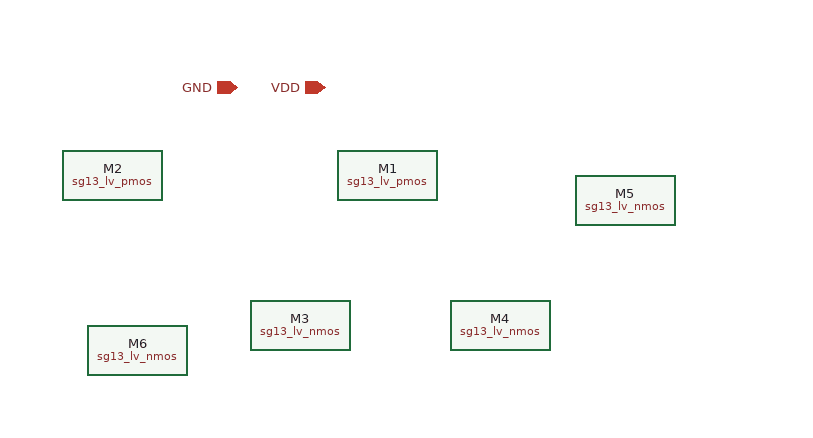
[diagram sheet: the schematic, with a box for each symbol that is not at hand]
v {xschem version=3.4.8RC file_version=1.2}
G {}
K {}
V {}
S {}
F {}
E {}
C {sg13g2_pr/sg13_lv_pmos.sym} 120 0 0 0 {name=M1
l=0.13u
w=0.15u
ng=1
m=1
model=sg13_lv_pmos
spiceprefix=X
}
C {sg13g2_pr/sg13_lv_pmos.sym} -100 0 0 0 {name=M2
l=0.13u
w=0.15u
ng=1
m=1
model=sg13_lv_pmos
spiceprefix=X
}
C {sg13g2_pr/sg13_lv_nmos.sym} 50 120 0 0 {name=M3
l=0.13u
w=0.15u
ng=1
m=1
model=sg13_lv_nmos
spiceprefix=X
}
C {sg13g2_pr/sg13_lv_nmos.sym} 210 120 0 0 {name=M4
l=0.13u
w=0.15u
ng=1
m=1
model=sg13_lv_nmos
spiceprefix=X
}
C {sg13g2_pr/sg13_lv_nmos.sym} 310 20 0 0 {name=M5
l=0.13u
w=0.15u
ng=1
m=1
model=sg13_lv_nmos
spiceprefix=X
}
C {sg13g2_pr/sg13_lv_nmos.sym} -80 140 0 0 {name=M6
l=0.13u
w=0.15u
ng=1
m=1
model=sg13_lv_nmos
spiceprefix=X
}
C {iopin.sym} 0 -70 0 0 {name=GND lab=GND}
C {iopin.sym} 70 -70 0 0 {name=VDD lab=VDD}
